VERSION 5.7 ;
  NOWIREEXTENSIONATPIN ON ;
  DIVIDERCHAR "/" ;
  BUSBITCHARS "[]" ;
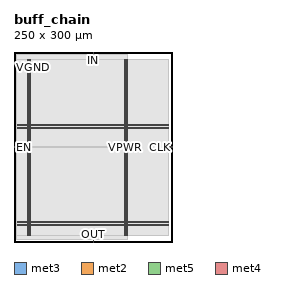
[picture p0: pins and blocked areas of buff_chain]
MACRO buff_chain
  CLASS BLOCK ;
  FOREIGN buff_chain ;
  ORIGIN 0.000 0.000 ;
  SIZE 250.000 BY 300.000 ;
  PIN CLK
    PORT
      LAYER met3 ;
        RECT 246.000 149.640 250.000 150.240 ;
    END
  END CLK
  PIN EN
    PORT
      LAYER met3 ;
        RECT 0.000 149.640 4.000 150.240 ;
    END
  END EN
  PIN IN
    PORT
      LAYER met2 ;
        RECT 124.750 296.000 125.030 300.000 ;
    END
  END IN
  PIN OUT
    PORT
      LAYER met2 ;
        RECT 124.750 0.000 125.030 4.000 ;
    END
  END OUT
  PIN VGND
    USE GROUND ;
    PORT
      LAYER met5 ;
        RECT 5.280 183.210 244.500 184.810 ;
    END
    PORT
      LAYER met5 ;
        RECT 5.280 30.030 244.500 31.630 ;
    END
    PORT
      LAYER met4 ;
        RECT 177.940 10.640 179.540 288.560 ;
    END
    PORT
      LAYER met4 ;
        RECT 24.340 10.640 25.940 288.560 ;
    END
  END VGND
  PIN VPWR
    USE POWER ;
    PORT
      LAYER met5 ;
        RECT 5.280 179.910 244.500 181.510 ;
    END
    PORT
      LAYER met5 ;
        RECT 5.280 26.730 244.500 28.330 ;
    END
    PORT
      LAYER met4 ;
        RECT 174.640 10.640 176.240 288.560 ;
    END
    PORT
      LAYER met4 ;
        RECT 21.040 10.640 22.640 288.560 ;
    END
  END VPWR
  OBS
      LAYER li1 ;
        RECT 5.520 10.795 244.260 288.405 ;
      LAYER met1 ;
        RECT 4.670 10.640 244.260 288.560 ;
      LAYER met2 ;
        RECT 4.690 295.720 124.470 296.210 ;
        RECT 125.310 295.720 179.510 296.210 ;
        RECT 4.690 4.280 179.510 295.720 ;
        RECT 4.690 4.000 124.470 4.280 ;
        RECT 125.310 4.000 179.510 4.280 ;
      LAYER met3 ;
        RECT 4.000 150.640 179.530 288.485 ;
        RECT 4.400 149.240 179.530 150.640 ;
        RECT 4.000 10.715 179.530 149.240 ;
  END
END buff_chain
END LIBRARY

